VERSION 5.7 ;
  NOWIREEXTENSIONATPIN ON ;
  DIVIDERCHAR "/" ;
  BUSBITCHARS "[]" ;
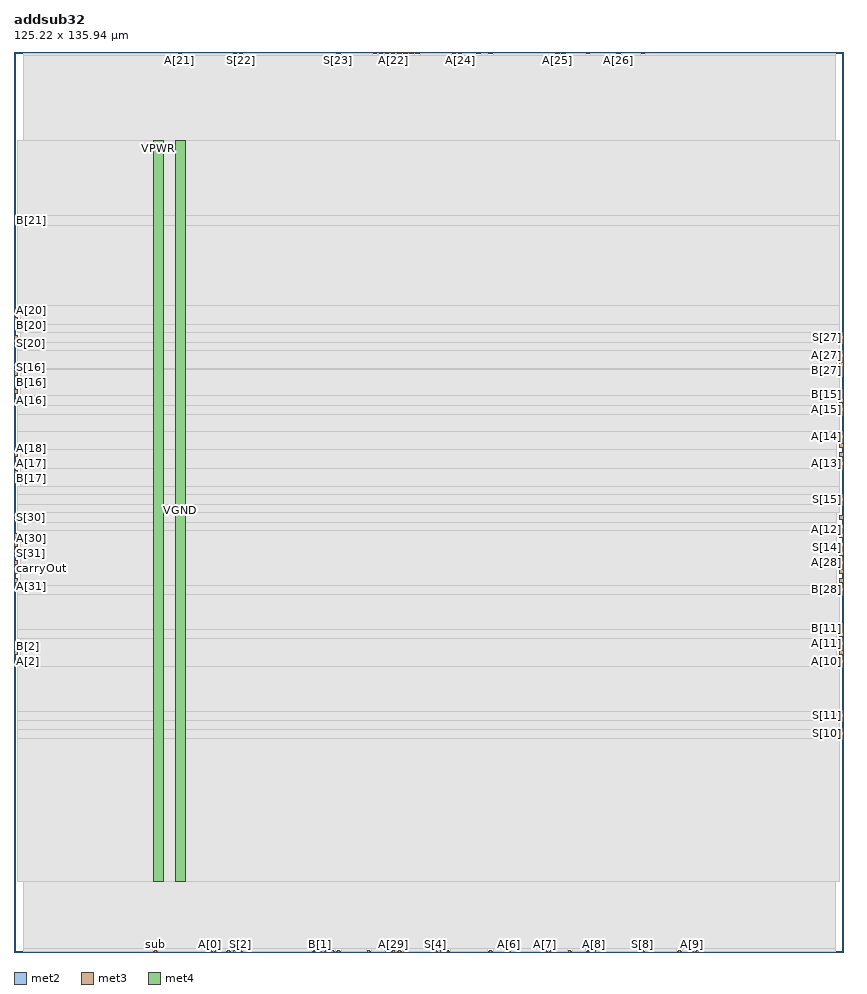
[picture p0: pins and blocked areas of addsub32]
MACRO addsub32
  CLASS BLOCK ;
  FOREIGN addsub32 ;
  ORIGIN 0.000 0.000 ;
  SIZE 125.220 BY 135.940 ;
  PIN A[0]
    DIRECTION INPUT ;
    USE SIGNAL ;
    ANTENNAGATEAREA 0.213000 ;
    PORT
      LAYER met2 ;
        RECT 29.530 0.000 29.810 0.280 ;
    END
  END A[0]
  PIN A[10]
    DIRECTION INPUT ;
    USE SIGNAL ;
    ANTENNAGATEAREA 0.213000 ;
    PORT
      LAYER met3 ;
        RECT 124.620 43.560 125.220 44.160 ;
    END
  END A[10]
  PIN A[11]
    DIRECTION INPUT ;
    USE SIGNAL ;
    ANTENNAGATEAREA 0.213000 ;
    PORT
      LAYER met3 ;
        RECT 124.620 46.280 125.220 46.880 ;
    END
  END A[11]
  PIN A[12]
    DIRECTION INPUT ;
    USE SIGNAL ;
    ANTENNAGATEAREA 0.213000 ;
    PORT
      LAYER met3 ;
        RECT 124.620 62.600 125.220 63.200 ;
    END
  END A[12]
  PIN A[13]
    DIRECTION INPUT ;
    USE SIGNAL ;
    ANTENNAGATEAREA 0.213000 ;
    PORT
      LAYER met3 ;
        RECT 124.620 73.480 125.220 74.080 ;
    END
  END A[13]
  PIN A[14]
    DIRECTION INPUT ;
    USE SIGNAL ;
    ANTENNAGATEAREA 0.213000 ;
    PORT
      LAYER met3 ;
        RECT 124.620 77.560 125.220 78.160 ;
    END
  END A[14]
  PIN A[15]
    DIRECTION INPUT ;
    USE SIGNAL ;
    ANTENNAGATEAREA 0.213000 ;
    PORT
      LAYER met3 ;
        RECT 124.620 81.640 125.220 82.240 ;
    END
  END A[15]
  PIN A[16]
    DIRECTION INPUT ;
    USE SIGNAL ;
    ANTENNAGATEAREA 0.213000 ;
    PORT
      LAYER met3 ;
        RECT 0.000 83.000 0.600 83.600 ;
    END
  END A[16]
  PIN A[17]
    DIRECTION INPUT ;
    USE SIGNAL ;
    ANTENNAGATEAREA 0.213000 ;
    PORT
      LAYER met3 ;
        RECT 0.000 73.480 0.600 74.080 ;
    END
  END A[17]
  PIN A[18]
    DIRECTION INPUT ;
    USE SIGNAL ;
    ANTENNAGATEAREA 0.213000 ;
    PORT
      LAYER met3 ;
        RECT 0.000 74.840 0.600 75.440 ;
    END
  END A[18]
  PIN A[19]
    DIRECTION INPUT ;
    USE SIGNAL ;
    ANTENNAGATEAREA 0.213000 ;
    PORT
      LAYER met2 ;
        RECT 55.290 135.660 55.570 135.940 ;
    END
  END A[19]
  PIN A[1]
    DIRECTION INPUT ;
    USE SIGNAL ;
    ANTENNAGATEAREA 0.213000 ;
    PORT
      LAYER met2 ;
        RECT 45.170 0.000 45.450 0.280 ;
    END
  END A[1]
  PIN A[20]
    DIRECTION INPUT ;
    USE SIGNAL ;
    ANTENNAGATEAREA 0.213000 ;
    PORT
      LAYER met3 ;
        RECT 0.000 96.600 0.600 97.200 ;
    END
  END A[20]
  PIN A[21]
    DIRECTION INPUT ;
    USE SIGNAL ;
    ANTENNAGATEAREA 0.213000 ;
    PORT
      LAYER met2 ;
        RECT 24.930 135.660 25.210 135.940 ;
    END
  END A[21]
  PIN A[22]
    DIRECTION INPUT ;
    USE SIGNAL ;
    ANTENNAGATEAREA 0.213000 ;
    PORT
      LAYER met2 ;
        RECT 57.130 135.660 57.410 135.940 ;
    END
  END A[22]
  PIN A[23]
    DIRECTION INPUT ;
    USE SIGNAL ;
    ANTENNAGATEAREA 0.213000 ;
    PORT
      LAYER met2 ;
        RECT 54.370 135.660 54.650 135.940 ;
    END
  END A[23]
  PIN A[24]
    DIRECTION INPUT ;
    USE SIGNAL ;
    ANTENNAGATEAREA 0.213000 ;
    PORT
      LAYER met2 ;
        RECT 67.250 135.660 67.530 135.940 ;
    END
  END A[24]
  PIN A[25]
    DIRECTION INPUT ;
    USE SIGNAL ;
    ANTENNAGATEAREA 0.213000 ;
    PORT
      LAYER met2 ;
        RECT 81.970 135.660 82.250 135.940 ;
    END
  END A[25]
  PIN A[26]
    DIRECTION INPUT ;
    USE SIGNAL ;
    ANTENNAGATEAREA 0.213000 ;
    PORT
      LAYER met2 ;
        RECT 91.170 135.660 91.450 135.940 ;
    END
  END A[26]
  PIN A[27]
    DIRECTION INPUT ;
    USE SIGNAL ;
    ANTENNAGATEAREA 0.213000 ;
    PORT
      LAYER met3 ;
        RECT 124.620 89.800 125.220 90.400 ;
    END
  END A[27]
  PIN A[28]
    DIRECTION INPUT ;
    USE SIGNAL ;
    ANTENNAGATEAREA 0.213000 ;
    PORT
      LAYER met3 ;
        RECT 124.620 58.520 125.220 59.120 ;
    END
  END A[28]
  PIN A[29]
    DIRECTION INPUT ;
    USE SIGNAL ;
    ANTENNAGATEAREA 0.213000 ;
    PORT
      LAYER met2 ;
        RECT 57.130 0.000 57.410 0.280 ;
    END
  END A[29]
  PIN A[2]
    DIRECTION INPUT ;
    USE SIGNAL ;
    ANTENNAGATEAREA 0.213000 ;
    PORT
      LAYER met3 ;
        RECT 0.000 43.560 0.600 44.160 ;
    END
  END A[2]
  PIN A[30]
    DIRECTION INPUT ;
    USE SIGNAL ;
    ANTENNAGATEAREA 0.213000 ;
    PORT
      LAYER met3 ;
        RECT 0.000 61.240 0.600 61.840 ;
    END
  END A[30]
  PIN A[31]
    DIRECTION INPUT ;
    USE SIGNAL ;
    ANTENNAGATEAREA 0.213000 ;
    PORT
      LAYER met3 ;
        RECT 0.000 55.800 0.600 56.400 ;
    END
  END A[31]
  PIN A[3]
    DIRECTION INPUT ;
    USE SIGNAL ;
    ANTENNAGATEAREA 0.213000 ;
    PORT
      LAYER met2 ;
        RECT 47.010 0.000 47.290 0.280 ;
    END
  END A[3]
  PIN A[4]
    DIRECTION INPUT ;
    USE SIGNAL ;
    ANTENNAGATEAREA 0.213000 ;
    PORT
      LAYER met2 ;
        RECT 56.210 0.000 56.490 0.280 ;
    END
  END A[4]
  PIN A[5]
    DIRECTION INPUT ;
    USE SIGNAL ;
    ANTENNAGATEAREA 0.213000 ;
    PORT
      LAYER met2 ;
        RECT 53.450 0.000 53.730 0.280 ;
    END
  END A[5]
  PIN A[6]
    DIRECTION INPUT ;
    USE SIGNAL ;
    ANTENNAGATEAREA 0.213000 ;
    PORT
      LAYER met2 ;
        RECT 74.610 0.000 74.890 0.280 ;
    END
  END A[6]
  PIN A[7]
    DIRECTION INPUT ;
    USE SIGNAL ;
    ANTENNAGATEAREA 0.213000 ;
    PORT
      LAYER met2 ;
        RECT 80.130 0.000 80.410 0.280 ;
    END
  END A[7]
  PIN A[8]
    DIRECTION INPUT ;
    USE SIGNAL ;
    ANTENNAGATEAREA 0.213000 ;
    PORT
      LAYER met2 ;
        RECT 87.490 0.000 87.770 0.280 ;
    END
  END A[8]
  PIN A[9]
    DIRECTION INPUT ;
    USE SIGNAL ;
    ANTENNAGATEAREA 0.213000 ;
    PORT
      LAYER met2 ;
        RECT 102.210 0.000 102.490 0.280 ;
    END
  END A[9]
  PIN B[0]
    DIRECTION INPUT ;
    USE SIGNAL ;
    ANTENNAGATEAREA 0.126000 ;
    PORT
      LAYER met2 ;
        RECT 30.450 0.000 30.730 0.280 ;
    END
  END B[0]
  PIN B[10]
    DIRECTION INPUT ;
    USE SIGNAL ;
    ANTENNAGATEAREA 0.213000 ;
    PORT
      LAYER met3 ;
        RECT 124.620 44.920 125.220 45.520 ;
    END
  END B[10]
  PIN B[11]
    DIRECTION INPUT ;
    USE SIGNAL ;
    ANTENNAGATEAREA 0.213000 ;
    PORT
      LAYER met3 ;
        RECT 124.620 47.640 125.220 48.240 ;
    END
  END B[11]
  PIN B[12]
    DIRECTION INPUT ;
    USE SIGNAL ;
    ANTENNAGATEAREA 0.213000 ;
    PORT
      LAYER met3 ;
        RECT 124.620 61.240 125.220 61.840 ;
    END
  END B[12]
  PIN B[13]
    DIRECTION INPUT ;
    USE SIGNAL ;
    ANTENNAGATEAREA 0.213000 ;
    PORT
      LAYER met3 ;
        RECT 124.620 74.840 125.220 75.440 ;
    END
  END B[13]
  PIN B[14]
    DIRECTION INPUT ;
    USE SIGNAL ;
    ANTENNAGATEAREA 0.213000 ;
    PORT
      LAYER met3 ;
        RECT 124.620 76.200 125.220 76.800 ;
    END
  END B[14]
  PIN B[15]
    DIRECTION INPUT ;
    USE SIGNAL ;
    ANTENNAGATEAREA 0.213000 ;
    PORT
      LAYER met3 ;
        RECT 124.620 83.000 125.220 83.600 ;
    END
  END B[15]
  PIN B[16]
    DIRECTION INPUT ;
    USE SIGNAL ;
    ANTENNAGATEAREA 0.213000 ;
    PORT
      LAYER met3 ;
        RECT 0.000 85.720 0.600 86.320 ;
    END
  END B[16]
  PIN B[17]
    DIRECTION INPUT ;
    USE SIGNAL ;
    ANTENNAGATEAREA 0.213000 ;
    PORT
      LAYER met3 ;
        RECT 0.000 72.120 0.600 72.720 ;
    END
  END B[17]
  PIN B[18]
    DIRECTION INPUT ;
    USE SIGNAL ;
    ANTENNAGATEAREA 0.213000 ;
    PORT
      LAYER met3 ;
        RECT 0.000 70.760 0.600 71.360 ;
    END
  END B[18]
  PIN B[19]
    DIRECTION INPUT ;
    USE SIGNAL ;
    ANTENNAGATEAREA 0.213000 ;
    PORT
      LAYER met2 ;
        RECT 60.810 135.660 61.090 135.940 ;
    END
  END B[19]
  PIN B[1]
    DIRECTION INPUT ;
    USE SIGNAL ;
    ANTENNAGATEAREA 0.213000 ;
    PORT
      LAYER met2 ;
        RECT 46.090 0.000 46.370 0.280 ;
    END
  END B[1]
  PIN B[20]
    DIRECTION INPUT ;
    USE SIGNAL ;
    ANTENNAGATEAREA 0.213000 ;
    PORT
      LAYER met3 ;
        RECT 0.000 95.240 0.600 95.840 ;
    END
  END B[20]
  PIN B[21]
    DIRECTION INPUT ;
    USE SIGNAL ;
    ANTENNAGATEAREA 0.213000 ;
    PORT
      LAYER met3 ;
        RECT 0.000 110.200 0.600 110.800 ;
    END
  END B[21]
  PIN B[22]
    DIRECTION INPUT ;
    USE SIGNAL ;
    ANTENNAGATEAREA 0.213000 ;
    PORT
      LAYER met2 ;
        RECT 58.970 135.660 59.250 135.940 ;
    END
  END B[22]
  PIN B[23]
    DIRECTION INPUT ;
    USE SIGNAL ;
    ANTENNAGATEAREA 0.213000 ;
    PORT
      LAYER met2 ;
        RECT 56.210 135.660 56.490 135.940 ;
    END
  END B[23]
  PIN B[24]
    DIRECTION INPUT ;
    USE SIGNAL ;
    ANTENNAGATEAREA 0.213000 ;
    PORT
      LAYER met2 ;
        RECT 66.330 135.660 66.610 135.940 ;
    END
  END B[24]
  PIN B[25]
    DIRECTION INPUT ;
    USE SIGNAL ;
    ANTENNAGATEAREA 0.213000 ;
    PORT
      LAYER met2 ;
        RECT 82.890 135.660 83.170 135.940 ;
    END
  END B[25]
  PIN B[26]
    DIRECTION INPUT ;
    USE SIGNAL ;
    ANTENNAGATEAREA 0.213000 ;
    PORT
      LAYER met2 ;
        RECT 94.850 135.660 95.130 135.940 ;
    END
  END B[26]
  PIN B[27]
    DIRECTION INPUT ;
    USE SIGNAL ;
    ANTENNAGATEAREA 0.213000 ;
    PORT
      LAYER met3 ;
        RECT 124.620 88.440 125.220 89.040 ;
    END
  END B[27]
  PIN B[28]
    DIRECTION INPUT ;
    USE SIGNAL ;
    ANTENNAGATEAREA 0.213000 ;
    PORT
      LAYER met3 ;
        RECT 124.620 54.440 125.220 55.040 ;
    END
  END B[28]
  PIN B[29]
    DIRECTION INPUT ;
    USE SIGNAL ;
    ANTENNAGATEAREA 0.213000 ;
    PORT
      LAYER met2 ;
        RECT 58.970 0.000 59.250 0.280 ;
    END
  END B[29]
  PIN B[2]
    DIRECTION INPUT ;
    USE SIGNAL ;
    ANTENNAGATEAREA 0.213000 ;
    PORT
      LAYER met3 ;
        RECT 0.000 44.920 0.600 45.520 ;
    END
  END B[2]
  PIN B[30]
    DIRECTION INPUT ;
    USE SIGNAL ;
    ANTENNAGATEAREA 0.213000 ;
    PORT
      LAYER met3 ;
        RECT 0.000 62.600 0.600 63.200 ;
    END
  END B[30]
  PIN B[31]
    DIRECTION INPUT ;
    USE SIGNAL ;
    ANTENNAGATEAREA 0.213000 ;
    PORT
      LAYER met3 ;
        RECT 0.000 57.160 0.600 57.760 ;
    END
  END B[31]
  PIN B[3]
    DIRECTION INPUT ;
    USE SIGNAL ;
    ANTENNAGATEAREA 0.213000 ;
    PORT
      LAYER met2 ;
        RECT 47.930 0.000 48.210 0.280 ;
    END
  END B[3]
  PIN B[4]
    DIRECTION INPUT ;
    USE SIGNAL ;
    ANTENNAGATEAREA 0.213000 ;
    PORT
      LAYER met2 ;
        RECT 58.050 0.000 58.330 0.280 ;
    END
  END B[4]
  PIN B[5]
    DIRECTION INPUT ;
    USE SIGNAL ;
    ANTENNAGATEAREA 0.213000 ;
    PORT
      LAYER met2 ;
        RECT 48.850 0.000 49.130 0.280 ;
    END
  END B[5]
  PIN B[6]
    DIRECTION INPUT ;
    USE SIGNAL ;
    ANTENNAGATEAREA 0.213000 ;
    PORT
      LAYER met2 ;
        RECT 71.850 0.000 72.130 0.280 ;
    END
  END B[6]
  PIN B[7]
    DIRECTION INPUT ;
    USE SIGNAL ;
    ANTENNAGATEAREA 0.213000 ;
    PORT
      LAYER met2 ;
        RECT 81.050 0.000 81.330 0.280 ;
    END
  END B[7]
  PIN B[8]
    DIRECTION INPUT ;
    USE SIGNAL ;
    ANTENNAGATEAREA 0.213000 ;
    PORT
      LAYER met2 ;
        RECT 86.570 0.000 86.850 0.280 ;
    END
  END B[8]
  PIN B[9]
    DIRECTION INPUT ;
    USE SIGNAL ;
    ANTENNAGATEAREA 0.213000 ;
    PORT
      LAYER met2 ;
        RECT 103.130 0.000 103.410 0.280 ;
    END
  END B[9]
  PIN S[0]
    DIRECTION OUTPUT ;
    USE SIGNAL ;
    ANTENNADIFFAREA 0.702900 ;
    PORT
      LAYER met2 ;
        RECT 32.290 0.000 32.570 0.280 ;
    END
  END S[0]
  PIN S[10]
    DIRECTION OUTPUT ;
    USE SIGNAL ;
    ANTENNADIFFAREA 1.336500 ;
    PORT
      LAYER met3 ;
        RECT 124.620 32.680 125.220 33.280 ;
    END
  END S[10]
  PIN S[11]
    DIRECTION OUTPUT ;
    USE SIGNAL ;
    ANTENNADIFFAREA 1.336500 ;
    PORT
      LAYER met3 ;
        RECT 124.620 35.400 125.220 36.000 ;
    END
  END S[11]
  PIN S[12]
    DIRECTION OUTPUT ;
    USE SIGNAL ;
    ANTENNADIFFAREA 1.336500 ;
    PORT
      LAYER met3 ;
        RECT 124.620 55.800 125.220 56.400 ;
    END
  END S[12]
  PIN S[13]
    DIRECTION OUTPUT ;
    USE SIGNAL ;
    ANTENNADIFFAREA 1.336500 ;
    PORT
      LAYER met3 ;
        RECT 124.620 57.160 125.220 57.760 ;
    END
  END S[13]
  PIN S[14]
    DIRECTION OUTPUT ;
    USE SIGNAL ;
    ANTENNADIFFAREA 1.336500 ;
    PORT
      LAYER met3 ;
        RECT 124.620 59.880 125.220 60.480 ;
    END
  END S[14]
  PIN S[15]
    DIRECTION OUTPUT ;
    USE SIGNAL ;
    ANTENNADIFFAREA 0.383400 ;
    PORT
      LAYER met3 ;
        RECT 124.620 68.040 125.220 68.640 ;
    END
  END S[15]
  PIN S[16]
    DIRECTION OUTPUT ;
    USE SIGNAL ;
    ANTENNADIFFAREA 1.336500 ;
    PORT
      LAYER met3 ;
        RECT 0.000 87.080 0.600 87.680 ;
    END
  END S[16]
  PIN S[17]
    DIRECTION OUTPUT ;
    USE SIGNAL ;
    ANTENNADIFFAREA 1.336500 ;
    PORT
      LAYER met3 ;
        RECT 0.000 84.360 0.600 84.960 ;
    END
  END S[17]
  PIN S[18]
    DIRECTION OUTPUT ;
    USE SIGNAL ;
    ANTENNADIFFAREA 0.445500 ;
    PORT
      LAYER met2 ;
        RECT 59.890 135.660 60.170 135.940 ;
    END
  END S[18]
  PIN S[19]
    DIRECTION OUTPUT ;
    USE SIGNAL ;
    ANTENNADIFFAREA 0.891000 ;
    PORT
      LAYER met2 ;
        RECT 58.050 135.660 58.330 135.940 ;
    END
  END S[19]
  PIN S[1]
    DIRECTION OUTPUT ;
    USE SIGNAL ;
    ANTENNADIFFAREA 1.336500 ;
    PORT
      LAYER met2 ;
        RECT 33.210 0.000 33.490 0.280 ;
    END
  END S[1]
  PIN S[20]
    DIRECTION OUTPUT ;
    USE SIGNAL ;
    ANTENNADIFFAREA 0.795200 ;
    PORT
      LAYER met3 ;
        RECT 0.000 92.520 0.600 93.120 ;
    END
  END S[20]
  PIN S[21]
    DIRECTION OUTPUT ;
    USE SIGNAL ;
    ANTENNADIFFAREA 1.782000 ;
    PORT
      LAYER met2 ;
        RECT 33.210 135.660 33.490 135.940 ;
    END
  END S[21]
  PIN S[22]
    DIRECTION OUTPUT ;
    USE SIGNAL ;
    ANTENNADIFFAREA 1.782000 ;
    PORT
      LAYER met2 ;
        RECT 34.130 135.660 34.410 135.940 ;
    END
  END S[22]
  PIN S[23]
    DIRECTION OUTPUT ;
    USE SIGNAL ;
    ANTENNADIFFAREA 1.336500 ;
    PORT
      LAYER met2 ;
        RECT 48.850 135.660 49.130 135.940 ;
    END
  END S[23]
  PIN S[24]
    DIRECTION OUTPUT ;
    USE SIGNAL ;
    ANTENNADIFFAREA 0.383400 ;
    PORT
      LAYER met2 ;
        RECT 70.010 135.660 70.290 135.940 ;
    END
  END S[24]
  PIN S[25]
    DIRECTION OUTPUT ;
    USE SIGNAL ;
    ANTENNADIFFAREA 0.383400 ;
    PORT
      LAYER met2 ;
        RECT 71.850 135.660 72.130 135.940 ;
    END
  END S[25]
  PIN S[26]
    DIRECTION OUTPUT ;
    USE SIGNAL ;
    ANTENNADIFFAREA 0.383400 ;
    PORT
      LAYER met2 ;
        RECT 86.570 135.660 86.850 135.940 ;
    END
  END S[26]
  PIN S[27]
    DIRECTION OUTPUT ;
    USE SIGNAL ;
    ANTENNADIFFAREA 0.891000 ;
    PORT
      LAYER met3 ;
        RECT 124.620 92.520 125.220 93.120 ;
    END
  END S[27]
  PIN S[28]
    DIRECTION OUTPUT ;
    USE SIGNAL ;
    ANTENNADIFFAREA 1.336500 ;
    PORT
      LAYER met3 ;
        RECT 124.620 63.960 125.220 64.560 ;
    END
  END S[28]
  PIN S[29]
    DIRECTION OUTPUT ;
    USE SIGNAL ;
    ANTENNADIFFAREA 1.336500 ;
    PORT
      LAYER met3 ;
        RECT 124.620 65.320 125.220 65.920 ;
    END
  END S[29]
  PIN S[2]
    DIRECTION OUTPUT ;
    USE SIGNAL ;
    ANTENNADIFFAREA 1.336500 ;
    PORT
      LAYER met2 ;
        RECT 34.130 0.000 34.410 0.280 ;
    END
  END S[2]
  PIN S[30]
    DIRECTION OUTPUT ;
    USE SIGNAL ;
    ANTENNADIFFAREA 1.336500 ;
    PORT
      LAYER met3 ;
        RECT 0.000 65.320 0.600 65.920 ;
    END
  END S[30]
  PIN S[31]
    DIRECTION OUTPUT ;
    USE SIGNAL ;
    ANTENNADIFFAREA 1.336500 ;
    PORT
      LAYER met3 ;
        RECT 0.000 59.880 0.600 60.480 ;
    END
  END S[31]
  PIN S[3]
    DIRECTION OUTPUT ;
    USE SIGNAL ;
    ANTENNADIFFAREA 1.782000 ;
    PORT
      LAYER met3 ;
        RECT 0.000 46.280 0.600 46.880 ;
    END
  END S[3]
  PIN S[4]
    DIRECTION OUTPUT ;
    USE SIGNAL ;
    ANTENNADIFFAREA 1.336500 ;
    PORT
      LAYER met2 ;
        RECT 63.570 0.000 63.850 0.280 ;
    END
  END S[4]
  PIN S[5]
    DIRECTION OUTPUT ;
    USE SIGNAL ;
    ANTENNADIFFAREA 1.336500 ;
    PORT
      LAYER met2 ;
        RECT 64.490 0.000 64.770 0.280 ;
    END
  END S[5]
  PIN S[6]
    DIRECTION OUTPUT ;
    USE SIGNAL ;
    ANTENNADIFFAREA 1.336500 ;
    PORT
      LAYER met2 ;
        RECT 65.410 0.000 65.690 0.280 ;
    END
  END S[6]
  PIN S[7]
    DIRECTION OUTPUT ;
    USE SIGNAL ;
    ANTENNADIFFAREA 1.336500 ;
    PORT
      LAYER met2 ;
        RECT 83.810 0.000 84.090 0.280 ;
    END
  END S[7]
  PIN S[8]
    DIRECTION OUTPUT ;
    USE SIGNAL ;
    ANTENNADIFFAREA 1.336500 ;
    PORT
      LAYER met2 ;
        RECT 94.850 0.000 95.130 0.280 ;
    END
  END S[8]
  PIN S[9]
    DIRECTION OUTPUT ;
    USE SIGNAL ;
    ANTENNADIFFAREA 1.336500 ;
    PORT
      LAYER met2 ;
        RECT 100.370 0.000 100.650 0.280 ;
    END
  END S[9]
  PIN VGND
    DIRECTION INOUT ;
    USE GROUND ;
    PORT
      LAYER met4 ;
        RECT 24.340 10.640 25.940 122.640 ;
    END
  END VGND
  PIN VPWR
    DIRECTION INOUT ;
    USE POWER ;
    PORT
      LAYER met4 ;
        RECT 21.040 10.640 22.640 122.640 ;
    END
  END VPWR
  PIN carryOut
    DIRECTION OUTPUT ;
    USE SIGNAL ;
    ANTENNADIFFAREA 1.336500 ;
    PORT
      LAYER met3 ;
        RECT 0.000 58.520 0.600 59.120 ;
    END
  END carryOut
  PIN sub
    DIRECTION INPUT ;
    USE SIGNAL ;
    ANTENNAGATEAREA 0.742500 ;
    PORT
      LAYER met2 ;
        RECT 21.250 0.000 21.530 0.280 ;
    END
  END sub
  OBS
      LAYER nwell ;
        RECT 5.330 10.795 119.790 122.590 ;
      LAYER li1 ;
        RECT 5.520 10.795 119.600 122.485 ;
      LAYER met1 ;
        RECT 1.450 2.760 124.130 122.640 ;
      LAYER met2 ;
        RECT 1.470 135.380 24.650 135.660 ;
        RECT 25.490 135.380 32.930 135.660 ;
        RECT 33.770 135.380 33.850 135.660 ;
        RECT 34.690 135.380 48.570 135.660 ;
        RECT 49.410 135.380 54.090 135.660 ;
        RECT 54.930 135.380 55.010 135.660 ;
        RECT 55.850 135.380 55.930 135.660 ;
        RECT 56.770 135.380 56.850 135.660 ;
        RECT 57.690 135.380 57.770 135.660 ;
        RECT 58.610 135.380 58.690 135.660 ;
        RECT 59.530 135.380 59.610 135.660 ;
        RECT 60.450 135.380 60.530 135.660 ;
        RECT 61.370 135.380 66.050 135.660 ;
        RECT 66.890 135.380 66.970 135.660 ;
        RECT 67.810 135.380 69.730 135.660 ;
        RECT 70.570 135.380 71.570 135.660 ;
        RECT 72.410 135.380 81.690 135.660 ;
        RECT 82.530 135.380 82.610 135.660 ;
        RECT 83.450 135.380 86.290 135.660 ;
        RECT 87.130 135.380 90.890 135.660 ;
        RECT 91.730 135.380 94.570 135.660 ;
        RECT 95.410 135.380 124.110 135.660 ;
        RECT 1.470 0.560 124.110 135.380 ;
        RECT 1.470 0.070 20.970 0.560 ;
        RECT 21.810 0.070 29.250 0.560 ;
        RECT 30.090 0.070 30.170 0.560 ;
        RECT 31.010 0.070 32.010 0.560 ;
        RECT 32.850 0.070 32.930 0.560 ;
        RECT 33.770 0.070 33.850 0.560 ;
        RECT 34.690 0.070 44.890 0.560 ;
        RECT 45.730 0.070 45.810 0.560 ;
        RECT 46.650 0.070 46.730 0.560 ;
        RECT 47.570 0.070 47.650 0.560 ;
        RECT 48.490 0.070 48.570 0.560 ;
        RECT 49.410 0.070 53.170 0.560 ;
        RECT 54.010 0.070 55.930 0.560 ;
        RECT 56.770 0.070 56.850 0.560 ;
        RECT 57.690 0.070 57.770 0.560 ;
        RECT 58.610 0.070 58.690 0.560 ;
        RECT 59.530 0.070 63.290 0.560 ;
        RECT 64.130 0.070 64.210 0.560 ;
        RECT 65.050 0.070 65.130 0.560 ;
        RECT 65.970 0.070 71.570 0.560 ;
        RECT 72.410 0.070 74.330 0.560 ;
        RECT 75.170 0.070 79.850 0.560 ;
        RECT 80.690 0.070 80.770 0.560 ;
        RECT 81.610 0.070 83.530 0.560 ;
        RECT 84.370 0.070 86.290 0.560 ;
        RECT 87.130 0.070 87.210 0.560 ;
        RECT 88.050 0.070 94.570 0.560 ;
        RECT 95.410 0.070 100.090 0.560 ;
        RECT 100.930 0.070 101.930 0.560 ;
        RECT 102.770 0.070 102.850 0.560 ;
        RECT 103.690 0.070 124.110 0.560 ;
      LAYER met3 ;
        RECT 0.600 111.200 124.620 122.565 ;
        RECT 1.000 109.800 124.620 111.200 ;
        RECT 0.600 97.600 124.620 109.800 ;
        RECT 1.000 94.840 124.620 97.600 ;
        RECT 0.600 93.520 124.620 94.840 ;
        RECT 1.000 92.120 124.220 93.520 ;
        RECT 0.600 90.800 124.620 92.120 ;
        RECT 0.600 88.080 124.220 90.800 ;
        RECT 1.000 88.040 124.220 88.080 ;
        RECT 1.000 84.000 124.620 88.040 ;
        RECT 1.000 82.600 124.220 84.000 ;
        RECT 0.600 81.240 124.220 82.600 ;
        RECT 0.600 78.560 124.620 81.240 ;
        RECT 0.600 75.840 124.220 78.560 ;
        RECT 1.000 73.080 124.220 75.840 ;
        RECT 1.000 70.360 124.620 73.080 ;
        RECT 0.600 69.040 124.620 70.360 ;
        RECT 0.600 67.640 124.220 69.040 ;
        RECT 0.600 66.320 124.620 67.640 ;
        RECT 1.000 64.920 124.220 66.320 ;
        RECT 0.600 63.600 124.220 64.920 ;
        RECT 1.000 55.400 124.220 63.600 ;
        RECT 0.600 54.040 124.220 55.400 ;
        RECT 0.600 48.640 124.620 54.040 ;
        RECT 0.600 47.280 124.220 48.640 ;
        RECT 1.000 43.160 124.220 47.280 ;
        RECT 0.600 36.400 124.620 43.160 ;
        RECT 0.600 35.000 124.220 36.400 ;
        RECT 0.600 33.680 124.620 35.000 ;
        RECT 0.600 32.280 124.220 33.680 ;
        RECT 0.600 10.715 124.620 32.280 ;
  END
END addsub32
END LIBRARY

